VERSION 5.7 ;
  NOWIREEXTENSIONATPIN ON ;
  DIVIDERCHAR "/" ;
  BUSBITCHARS "[]" ;
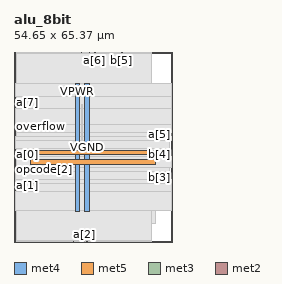
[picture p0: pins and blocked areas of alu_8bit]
MACRO alu_8bit
  CLASS BLOCK ;
  FOREIGN alu_8bit ;
  ORIGIN 0.000 0.000 ;
  SIZE 54.650 BY 65.370 ;
  PIN VGND
    DIRECTION INOUT ;
    USE GROUND ;
    PORT
      LAYER met4 ;
        RECT 24.340 10.640 25.940 54.640 ;
    END
    PORT
      LAYER met5 ;
        RECT 5.520 30.030 48.760 31.630 ;
    END
  END VGND
  PIN VPWR
    DIRECTION INOUT ;
    USE POWER ;
    PORT
      LAYER met4 ;
        RECT 21.040 10.640 22.640 54.640 ;
    END
    PORT
      LAYER met5 ;
        RECT 5.520 26.730 48.760 28.330 ;
    END
  END VPWR
  PIN a[0]
    DIRECTION INPUT ;
    USE SIGNAL ;
    ANTENNAGATEAREA 0.213000 ;
    PORT
      LAYER met3 ;
        RECT 0.000 29.960 0.600 30.560 ;
    END
  END a[0]
  PIN a[1]
    DIRECTION INPUT ;
    USE SIGNAL ;
    ANTENNAGATEAREA 0.213000 ;
    PORT
      LAYER met3 ;
        RECT 0.000 19.080 0.600 19.680 ;
    END
  END a[1]
  PIN a[2]
    DIRECTION INPUT ;
    USE SIGNAL ;
    ANTENNAGATEAREA 0.213000 ;
    PORT
      LAYER met2 ;
        RECT 24.010 0.000 24.290 0.280 ;
    END
  END a[2]
  PIN a[3]
    DIRECTION INPUT ;
    USE SIGNAL ;
    ANTENNAGATEAREA 0.213000 ;
    PORT
      LAYER met3 ;
        RECT 54.050 23.160 54.650 23.760 ;
    END
  END a[3]
  PIN a[4]
    DIRECTION INPUT ;
    USE SIGNAL ;
    ANTENNAGATEAREA 0.213000 ;
    PORT
      LAYER met3 ;
        RECT 54.050 31.320 54.650 31.920 ;
    END
  END a[4]
  PIN a[5]
    DIRECTION INPUT ;
    USE SIGNAL ;
    ANTENNAGATEAREA 0.213000 ;
    PORT
      LAYER met3 ;
        RECT 54.050 36.760 54.650 37.360 ;
    END
  END a[5]
  PIN a[6]
    DIRECTION INPUT ;
    USE SIGNAL ;
    ANTENNAGATEAREA 0.213000 ;
    PORT
      LAYER met2 ;
        RECT 27.690 65.090 27.970 65.370 ;
    END
  END a[6]
  PIN a[7]
    DIRECTION INPUT ;
    USE SIGNAL ;
    ANTENNAGATEAREA 0.213000 ;
    PORT
      LAYER met3 ;
        RECT 0.000 47.640 0.600 48.240 ;
    END
  END a[7]
  PIN b[0]
    DIRECTION INPUT ;
    USE SIGNAL ;
    ANTENNAGATEAREA 0.213000 ;
    PORT
      LAYER met3 ;
        RECT 0.000 28.600 0.600 29.200 ;
    END
  END b[0]
  PIN b[1]
    DIRECTION INPUT ;
    USE SIGNAL ;
    ANTENNAGATEAREA 0.213000 ;
    PORT
      LAYER met3 ;
        RECT 0.000 17.720 0.600 18.320 ;
    END
  END b[1]
  PIN b[2]
    DIRECTION INPUT ;
    USE SIGNAL ;
    ANTENNAGATEAREA 0.213000 ;
    PORT
      LAYER met2 ;
        RECT 24.930 0.000 25.210 0.280 ;
    END
  END b[2]
  PIN b[3]
    DIRECTION INPUT ;
    USE SIGNAL ;
    ANTENNAGATEAREA 0.213000 ;
    PORT
      LAYER met3 ;
        RECT 54.050 21.800 54.650 22.400 ;
    END
  END b[3]
  PIN b[4]
    DIRECTION INPUT ;
    USE SIGNAL ;
    ANTENNAGATEAREA 0.213000 ;
    PORT
      LAYER met3 ;
        RECT 54.050 29.960 54.650 30.560 ;
    END
  END b[4]
  PIN b[5]
    DIRECTION INPUT ;
    USE SIGNAL ;
    ANTENNAGATEAREA 0.213000 ;
    PORT
      LAYER met2 ;
        RECT 36.890 65.090 37.170 65.370 ;
    END
  END b[5]
  PIN b[6]
    DIRECTION INPUT ;
    USE SIGNAL ;
    ANTENNAGATEAREA 0.213000 ;
    PORT
      LAYER met2 ;
        RECT 23.090 65.090 23.370 65.370 ;
    END
  END b[6]
  PIN b[7]
    DIRECTION INPUT ;
    USE SIGNAL ;
    ANTENNAGATEAREA 0.213000 ;
    PORT
      LAYER met3 ;
        RECT 0.000 49.000 0.600 49.600 ;
    END
  END b[7]
  PIN opcode[0]
    DIRECTION INPUT ;
    USE SIGNAL ;
    ANTENNAGATEAREA 0.213000 ;
    PORT
      LAYER met3 ;
        RECT 0.000 31.320 0.600 31.920 ;
    END
  END opcode[0]
  PIN opcode[1]
    DIRECTION INPUT ;
    USE SIGNAL ;
    ANTENNAGATEAREA 0.495000 ;
    PORT
      LAYER met3 ;
        RECT 0.000 46.280 0.600 46.880 ;
    END
  END opcode[1]
  PIN opcode[2]
    DIRECTION INPUT ;
    USE SIGNAL ;
    ANTENNAGATEAREA 0.213000 ;
    PORT
      LAYER met3 ;
        RECT 0.000 27.240 0.600 27.840 ;
    END
  END opcode[2]
  PIN overflow
    DIRECTION OUTPUT ;
    USE SIGNAL ;
    ANTENNADIFFAREA 1.782000 ;
    PORT
      LAYER met3 ;
        RECT 0.000 39.480 0.600 40.080 ;
    END
  END overflow
  PIN result[0]
    DIRECTION OUTPUT ;
    USE SIGNAL ;
    ANTENNADIFFAREA 0.702900 ;
    PORT
      LAYER met3 ;
        RECT 0.000 25.880 0.600 26.480 ;
    END
  END result[0]
  PIN result[1]
    DIRECTION OUTPUT ;
    USE SIGNAL ;
    ANTENNADIFFAREA 0.702900 ;
    PORT
      LAYER met3 ;
        RECT 0.000 24.520 0.600 25.120 ;
    END
  END result[1]
  PIN result[2]
    DIRECTION OUTPUT ;
    USE SIGNAL ;
    ANTENNADIFFAREA 0.702900 ;
    PORT
      LAYER met2 ;
        RECT 20.330 0.000 20.610 0.280 ;
    END
  END result[2]
  PIN result[3]
    DIRECTION OUTPUT ;
    USE SIGNAL ;
    ANTENNADIFFAREA 0.702900 ;
    PORT
      LAYER met3 ;
        RECT 54.050 24.520 54.650 25.120 ;
    END
  END result[3]
  PIN result[4]
    DIRECTION OUTPUT ;
    USE SIGNAL ;
    ANTENNADIFFAREA 0.702900 ;
    PORT
      LAYER met3 ;
        RECT 54.050 32.680 54.650 33.280 ;
    END
  END result[4]
  PIN result[5]
    DIRECTION OUTPUT ;
    USE SIGNAL ;
    ANTENNAGATEAREA 0.126000 ;
    ANTENNADIFFAREA 0.429000 ;
    PORT
      LAYER met3 ;
        RECT 54.050 34.040 54.650 34.640 ;
    END
  END result[5]
  PIN result[6]
    DIRECTION OUTPUT ;
    USE SIGNAL ;
    ANTENNAGATEAREA 0.126000 ;
    ANTENNADIFFAREA 0.429000 ;
    PORT
      LAYER met2 ;
        RECT 25.850 65.090 26.130 65.370 ;
    END
  END result[6]
  PIN result[7]
    DIRECTION OUTPUT ;
    USE SIGNAL ;
    ANTENNADIFFAREA 1.336500 ;
    PORT
      LAYER met3 ;
        RECT 0.000 38.120 0.600 38.720 ;
    END
  END result[7]
  PIN zero
    DIRECTION OUTPUT ;
    USE SIGNAL ;
    ANTENNADIFFAREA 1.336500 ;
    PORT
      LAYER met3 ;
        RECT 0.000 36.760 0.600 37.360 ;
    END
  END zero
  OBS
      LAYER nwell ;
        RECT 5.330 10.795 48.950 54.485 ;
      LAYER li1 ;
        RECT 5.520 10.795 48.760 54.485 ;
      LAYER met1 ;
        RECT 0.990 6.500 48.760 54.640 ;
      LAYER met2 ;
        RECT 1.010 64.810 22.810 65.090 ;
        RECT 23.650 64.810 25.570 65.090 ;
        RECT 26.410 64.810 27.410 65.090 ;
        RECT 28.250 64.810 36.610 65.090 ;
        RECT 37.450 64.810 47.290 65.090 ;
        RECT 1.010 0.560 47.290 64.810 ;
        RECT 1.010 0.070 20.050 0.560 ;
        RECT 20.890 0.070 23.730 0.560 ;
        RECT 24.570 0.070 24.650 0.560 ;
        RECT 25.490 0.070 47.290 0.560 ;
      LAYER met3 ;
        RECT 0.600 50.000 54.050 54.565 ;
        RECT 1.000 45.880 54.050 50.000 ;
        RECT 0.600 40.480 54.050 45.880 ;
        RECT 1.000 37.760 54.050 40.480 ;
        RECT 1.000 36.360 53.650 37.760 ;
        RECT 0.600 35.040 54.050 36.360 ;
        RECT 0.600 32.320 53.650 35.040 ;
        RECT 1.000 29.560 53.650 32.320 ;
        RECT 1.000 25.520 54.050 29.560 ;
        RECT 1.000 24.120 53.650 25.520 ;
        RECT 0.600 21.400 53.650 24.120 ;
        RECT 0.600 20.080 54.050 21.400 ;
        RECT 1.000 17.320 54.050 20.080 ;
        RECT 0.600 10.715 54.050 17.320 ;
      LAYER met4 ;
        RECT 23.295 33.495 23.625 47.425 ;
  END
END alu_8bit
END LIBRARY

